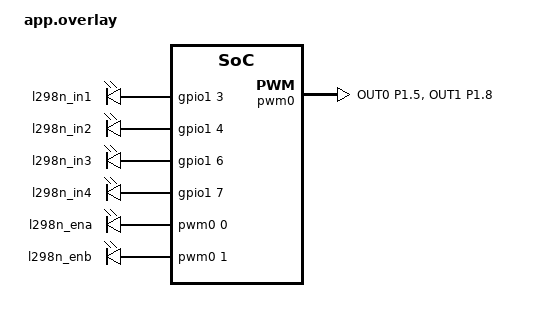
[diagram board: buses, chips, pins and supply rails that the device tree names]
#include <zephyr/dt-bindings/pwm/pwm.h>

/ {
    aliases {
        l298n-in1 = &l298n_in1;
        l298n-in2 = &l298n_in2;
        l298n-ena = &l298n_ena;
        l298n-in3 = &l298n_in3;
        l298n-in4 = &l298n_in4;
        l298n-enb = &l298n_enb;
    };

    l298n_pins {
        compatible = "gpio-leds";
        l298n_in1: l298n_in1 {
            gpios = <&gpio1 3 GPIO_ACTIVE_HIGH>;
        };
        l298n_in2: l298n_in2 {
            gpios = <&gpio1 4 GPIO_ACTIVE_HIGH>;
        };
        l298n_in3: l298n_in3 {
            gpios = <&gpio1 6 GPIO_ACTIVE_HIGH>;
        };
        l298n_in4: l298n_in4 {
            gpios = <&gpio1 7 GPIO_ACTIVE_HIGH>;
        };
    };

    pwm_leds {
        compatible = "pwm-leds";
        l298n_ena: l298n_ena {
            pwms = <&pwm0 0 PWM_MSEC(1) PWM_POLARITY_NORMAL>;
        };
        l298n_enb: l298n_enb {
            pwms = <&pwm0 1 PWM_MSEC(1) PWM_POLARITY_NORMAL>;
        };
    };
};

&pinctrl {
    pwm0_default: pwm0_default {
        group1 {
            psels = <NRF_PSEL(PWM_OUT0, 1, 5)>,
                    <NRF_PSEL(PWM_OUT1, 1, 8)>;
        };
    };

    pwm0_sleep: pwm0_sleep {
        group1 {
            psels = <NRF_PSEL(PWM_OUT0, 1, 5)>,
                    <NRF_PSEL(PWM_OUT1, 1, 8)>;
            low-power-enable;
        };
    };
};

&pwm0 {
    status = "okay";
    pinctrl-0 = <&pwm0_default>;
    pinctrl-1 = <&pwm0_sleep>;
    pinctrl-names = "default", "sleep";
};
